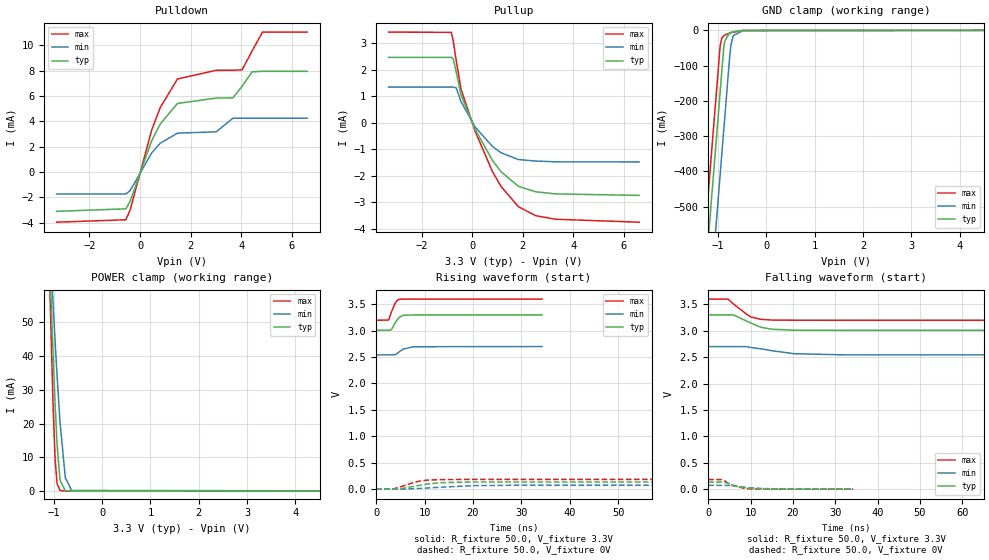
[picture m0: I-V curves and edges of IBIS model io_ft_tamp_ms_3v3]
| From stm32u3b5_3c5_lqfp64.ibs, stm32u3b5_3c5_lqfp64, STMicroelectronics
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[Model]   io_ft_tamp_ms_3v3
Model_type I/O
Polarity   Non-Inverting
Enable   Active-Low
| CAP_THRESHOLD on pad IOFT is "UDTCAPC" :
| Rising=30.0% of vddios   Falling=70.0% of vddios
| C_comp min and max val. don't necessarily correlate with the min and max pvt
| but are the smallest and greatest pad capacitance found.
| var   typ   min   max
C_comp   2.94735pF  2.92643pF  3.00915pF
|C_comp_pullup   1.82364pF  1.69750pF  1.79001pF
|C_comp_pulldown   1.12371pF  1.22892pF  1.21913pF
Vinl = 1.35V
Vinh = 1.8V
Vmeas = 1.65V   | Reference voltage for timing measurements
Cref  = 50.0pF   | Timing specification test load capacitance value
Rref  = 1.0MOhm   | Timing specification test load resistance value
Vref  = 1.815V   | Timing specification test load voltage
[Model Spec]
| TIME_THRESHOLD on pin ZIV11 is "CMOS" :
| Rising=50.0% of vdd   Falling=50.0% of vdd
Vinl 1.27950V 1.06950V 1.36550V
Vinh 1.78950V 1.51350V 1.89450V
| variable   typ   min   max
[Temperature Range] 25.0 130.0 -40.0
| variable   typ   min   max
[Voltage Range] 3.3V 2.7V 3.6V
| variable   typ   min   max
[POWER Clamp Reference] 3.3V 2.7V 3.6V
| variable   typ   min   max
[GND Clamp Reference] 0V 0V 0V
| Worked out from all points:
|   slope of the pulldown table from 0 to 0.495 V, typ, clamps not added: 190 ohm
|   slope of the pullup table from 0 to 0.495 V, typ, clamps not added: 524 ohm
|   GND clamp passes 1 mA (typ) near -0.53 V on its own axis
|   POWER clamp passes 1 mA (typ) near -0.83 V on its own axis
|   rising waveform, R_fixture 50.0, V_fixture 3.3V: 20-80 % time 1.22ns typ, 1.65ns min, 1.04ns max; typ from 3.01 V to 3.3 V
|   falling waveform, R_fixture 50.0, V_fixture 3.3V: 20-80 % time 4.97ns typ, 7.75ns min, 3.93ns max; typ from 3.3 V to 3.01 V
|   rising waveform, R_fixture 50.0, V_fixture 0V: 20-80 % time 5.2ns typ, 8.53ns min, 3.85ns max; typ from 0 V to 0.134 V
|   falling waveform, R_fixture 50.0, V_fixture 0V: 20-80 % time 3.95ns typ, 5.99ns min, 3.15ns max; typ from 0.134 V to 0 V
[POWER Clamp]
-3.3V     1.126A     769.5mA    1.647A
-1.1V     75.38mA    79.63mA    73.18mA
-1.09V    71.2mA     76.8mA     67.14mA
-1.08V    67.05mA    73.98mA    61.2mA
-1.06V    58.89mA    68.38mA    49.67mA
-1.01V    39.47mA    54.71mA    24.03mA
-970mV    25.49mA    44.18mA    9.257mA
-930mV    13.81mA    34.16mA    2.168mA
-870mV    3.251mA    20.56mA    140.6uA
-760mV    67.19uA    3.98mA     739.7nA
-630mV    518.2nA    149.1uA    1.746nA
6.6V      0A         0A         0A
[GND Clamp]
-3.3V     -4.165A    -4.4A      -4.034A
-1.25V    -679.9mA   -915.1mA   -549mA
-960mV    -186.9mA   -422.1mA   -55.97mA
-950mV    -169.9mA   -405.1mA   -42.45mA
-920mV    -118.9mA   -354.1mA   -22.92mA
-880mV    -51.66mA   -286.1mA   -15.35mA
-860mV    -30.97mA   -252.1mA   -13.65mA
-760mV    -7.32mA    -82.07mA   -8.144mA
-730mV    -5.898mA   -41.75mA   -6.789mA
-680mV    -4.176mA   -14.72mA   -4.769mA
-480mV    -457.9uA   -835.7uA   -334.7uA
6.6V      1.896nA    294.7nA    697.8pA
| variable   typ   min   max
[Pullup Reference] 3.3V 2.7V 3.6V
| variable   typ   min   max
[Pulldown Reference] 0V 0V 0V
[Pullup]
-3.3V     2.462mA    1.343mA    3.414mA
-820mV    2.462mA    1.343mA    3.403mA
-750mV    2.412mA    1.343mA    3.101mA
-630mV    1.919mA    1.316mA    2.34mA
-440mV    1.052mA    796.7uA    1.264mA
120mV     -252.2uA   -163.5uA   -324.6uA
800mV     -1.419mA   -890.9uA   -1.837mA
1.14V     -1.842mA   -1.132mA   -2.397mA
1.83V     -2.397mA   -1.387mA   -3.165mA
2.51V     -2.601mA   -1.443mA   -3.501mA
3.3V      -2.682mA   -1.473mA   -3.636mA
6.6V      -2.737mA   -1.478mA   -3.747mA
[Pulldown]
-3.3V     -3.112mA   -1.746mA   -3.972mA
-560mV    -2.917mA   -1.746mA   -3.78mA
-390mV    -2.313mA   -1.474mA   -2.998mA
460mV     2.475mA    1.504mA    3.307mA
800mV     3.8mA      2.27mA     5.099mA
1.48V     5.408mA    3.066mA    7.346mA
3.01V     5.836mA    3.17mA     8.031mA
3.67V     5.851mA    4.245mA    8.032mA
4.03V     6.763mA    4.245mA    8.067mA
4.43V     7.913mA    4.245mA    9.564mA
4.84V     7.948mA    4.245mA    11.05mA
6.6V      7.948mA    4.245mA    11.05mA
[Ramp]
dV/dt_r 80.15024mV/5.11898ns 43.44338mV/8.23578ns 109.51887mV/3.85643ns
dV/dt_f 175.11866mV/4.96903ns 94.57081mV/7.59281ns 240.98488mV/3.92282ns
R_load = 50.0
| Removed startup time: 0s 0s 0s  .
| Removed end time: 34.25ns.
[Rising Waveform]
R_fixture   = 50.0
V_fixture   = 3.3V
V_fixture_min = 2.7V
V_fixture_max = 3.6V
0s        3.008V     2.542V     3.198V
2.55ns    3.008V     2.542V     3.202V
2.7ns     3.008V     2.542V     3.229V
3.15ns    3.018V     2.542V     3.352V
3.9ns     3.146V     2.544V     3.515V
4.35ns    3.206V     2.57V      3.576V
4.8ns     3.254V     2.604V     3.595V
5.6ns     3.294V     2.651V     3.599V
7.7ns     3.299V     2.697V     3.599V
34.25ns   3.3V       2.7V       3.6V
| Removed startup time: 0s 0s 0s  .
| Removed end time: 199.25ns.
[Falling Waveform]
R_fixture   = 50.0
V_fixture   = 3.3V
V_fixture_min = 2.7V
V_fixture_max = 3.6V
0s        3.3V       2.7V       3.6V
4.7ns     3.301V     2.7V       3.599V
6.05ns    3.298V     2.7V       3.501V
9.05ns    3.183V     2.699V     3.314V
10.05ns   3.148V     2.684V     3.263V
12.35ns   3.068V     2.658V     3.217V
15.05ns   3.028V     2.622V     3.203V
20.35ns   3.01V      2.565V     3.199V
32.55ns   3.008V     2.543V     3.198V
199.3ns   3.008V     2.542V     3.198V
| Removed startup time: 0s 0s 0s  .
| Removed end time: 199.2ns.
[Rising Waveform]
R_fixture   = 50.0
V_fixture   = 0V
V_fixture_min = 0V
V_fixture_max = 0V
0s        42.36nV    238.8nV    101.2nV
3.4ns     -2.608mV   19.86uV    -1.781mV
5.2ns     8.499mV    -1.36mV    45.71mV
7.7ns     48.33mV    5.24mV     120.3mV
8.95ns    69.1mV     11.01mV    149.4mV
10.65ns   96.67mV    19.77mV    169.4mV
13.35ns   120.7mV    35.43mV    179.6mV
20.35ns   132.8mV    64.23mV    182.5mV
28.45ns   133.5mV    71.27mV    182.5mV
199.2ns   133.6mV    72.41mV    182.5mV
| Removed startup time: 0s 0s 0s  .
| Removed end time: 34.25ns.
[Falling Waveform]
R_fixture   = 50.0
V_fixture   = 0V
V_fixture_min = 0V
V_fixture_max = 0V
0s        133.6mV    72.41mV    182.5mV
3.2ns     133.6mV    72.41mV    182mV
3.9ns     130.3mV    72.4mV     156.9mV
5.1ns     98.78mV    69.99mV    93.49mV
6.15ns    67.39mV    59.42mV    60.85mV
8.2ns     33.17mV    39.03mV    22.09mV
10.2ns    13.64mV    24.24mV    2.637mV
12.6ns    1.273mV    13.24mV    310.7uV
17.5ns    117.4uV    1.074mV    31.53uV
34.25ns   315.2nV    10.19uV    202.3nV
